VERSION 5.7 ;
BUSBITCHARS "[]" ;
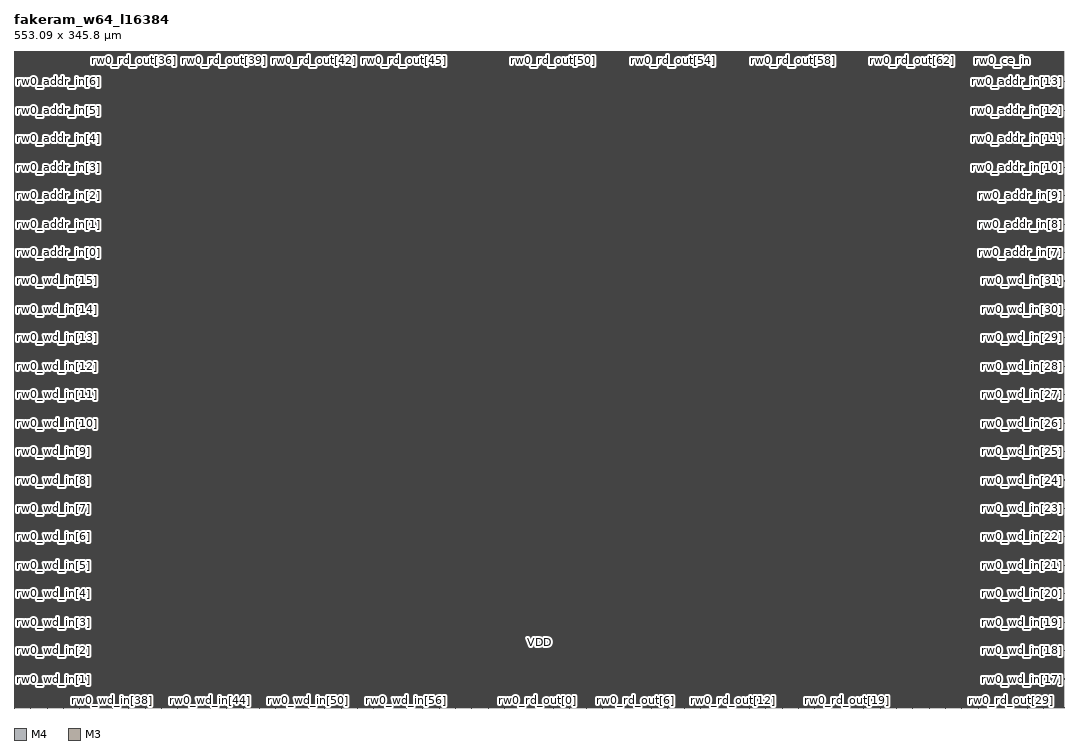
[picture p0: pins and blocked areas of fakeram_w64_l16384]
MACRO fakeram_w64_l16384
  FOREIGN fakeram_w64_l16384 0 0 ;
  SYMMETRY X Y R90 ;
  SIZE 553.090 BY 345.800 ;
  CLASS BLOCK ;
  PIN rw0_wd_in[0]
    DIRECTION INPUT ;
    USE SIGNAL ;
    SHAPE ABUTMENT ;
    PORT
      LAYER M4 ;
      RECT 0.000 0.276 0.072 0.300 ;
    END
  END rw0_wd_in[0]
  PIN rw0_wd_in[1]
    DIRECTION INPUT ;
    USE SIGNAL ;
    SHAPE ABUTMENT ;
    PORT
      LAYER M4 ;
      RECT 0.000 15.252 0.072 15.276 ;
    END
  END rw0_wd_in[1]
  PIN rw0_wd_in[2]
    DIRECTION INPUT ;
    USE SIGNAL ;
    SHAPE ABUTMENT ;
    PORT
      LAYER M4 ;
      RECT 0.000 30.228 0.072 30.252 ;
    END
  END rw0_wd_in[2]
  PIN rw0_wd_in[3]
    DIRECTION INPUT ;
    USE SIGNAL ;
    SHAPE ABUTMENT ;
    PORT
      LAYER M4 ;
      RECT 0.000 45.204 0.072 45.228 ;
    END
  END rw0_wd_in[3]
  PIN rw0_wd_in[4]
    DIRECTION INPUT ;
    USE SIGNAL ;
    SHAPE ABUTMENT ;
    PORT
      LAYER M4 ;
      RECT 0.000 60.180 0.072 60.204 ;
    END
  END rw0_wd_in[4]
  PIN rw0_wd_in[5]
    DIRECTION INPUT ;
    USE SIGNAL ;
    SHAPE ABUTMENT ;
    PORT
      LAYER M4 ;
      RECT 0.000 75.156 0.072 75.180 ;
    END
  END rw0_wd_in[5]
  PIN rw0_wd_in[6]
    DIRECTION INPUT ;
    USE SIGNAL ;
    SHAPE ABUTMENT ;
    PORT
      LAYER M4 ;
      RECT 0.000 90.132 0.072 90.156 ;
    END
  END rw0_wd_in[6]
  PIN rw0_wd_in[7]
    DIRECTION INPUT ;
    USE SIGNAL ;
    SHAPE ABUTMENT ;
    PORT
      LAYER M4 ;
      RECT 0.000 105.108 0.072 105.132 ;
    END
  END rw0_wd_in[7]
  PIN rw0_wd_in[8]
    DIRECTION INPUT ;
    USE SIGNAL ;
    SHAPE ABUTMENT ;
    PORT
      LAYER M4 ;
      RECT 0.000 120.084 0.072 120.108 ;
    END
  END rw0_wd_in[8]
  PIN rw0_wd_in[9]
    DIRECTION INPUT ;
    USE SIGNAL ;
    SHAPE ABUTMENT ;
    PORT
      LAYER M4 ;
      RECT 0.000 135.060 0.072 135.084 ;
    END
  END rw0_wd_in[9]
  PIN rw0_wd_in[10]
    DIRECTION INPUT ;
    USE SIGNAL ;
    SHAPE ABUTMENT ;
    PORT
      LAYER M4 ;
      RECT 0.000 150.036 0.072 150.060 ;
    END
  END rw0_wd_in[10]
  PIN rw0_wd_in[11]
    DIRECTION INPUT ;
    USE SIGNAL ;
    SHAPE ABUTMENT ;
    PORT
      LAYER M4 ;
      RECT 0.000 165.012 0.072 165.036 ;
    END
  END rw0_wd_in[11]
  PIN rw0_wd_in[12]
    DIRECTION INPUT ;
    USE SIGNAL ;
    SHAPE ABUTMENT ;
    PORT
      LAYER M4 ;
      RECT 0.000 179.988 0.072 180.012 ;
    END
  END rw0_wd_in[12]
  PIN rw0_wd_in[13]
    DIRECTION INPUT ;
    USE SIGNAL ;
    SHAPE ABUTMENT ;
    PORT
      LAYER M4 ;
      RECT 0.000 194.964 0.072 194.988 ;
    END
  END rw0_wd_in[13]
  PIN rw0_wd_in[14]
    DIRECTION INPUT ;
    USE SIGNAL ;
    SHAPE ABUTMENT ;
    PORT
      LAYER M4 ;
      RECT 0.000 209.940 0.072 209.964 ;
    END
  END rw0_wd_in[14]
  PIN rw0_wd_in[15]
    DIRECTION INPUT ;
    USE SIGNAL ;
    SHAPE ABUTMENT ;
    PORT
      LAYER M4 ;
      RECT 0.000 224.916 0.072 224.940 ;
    END
  END rw0_wd_in[15]
  PIN rw0_wd_in[16]
    DIRECTION INPUT ;
    USE SIGNAL ;
    SHAPE ABUTMENT ;
    PORT
      LAYER M4 ;
      RECT 553.018 0.276 553.090 0.300 ;
    END
  END rw0_wd_in[16]
  PIN rw0_wd_in[17]
    DIRECTION INPUT ;
    USE SIGNAL ;
    SHAPE ABUTMENT ;
    PORT
      LAYER M4 ;
      RECT 553.018 15.252 553.090 15.276 ;
    END
  END rw0_wd_in[17]
  PIN rw0_wd_in[18]
    DIRECTION INPUT ;
    USE SIGNAL ;
    SHAPE ABUTMENT ;
    PORT
      LAYER M4 ;
      RECT 553.018 30.228 553.090 30.252 ;
    END
  END rw0_wd_in[18]
  PIN rw0_wd_in[19]
    DIRECTION INPUT ;
    USE SIGNAL ;
    SHAPE ABUTMENT ;
    PORT
      LAYER M4 ;
      RECT 553.018 45.204 553.090 45.228 ;
    END
  END rw0_wd_in[19]
  PIN rw0_wd_in[20]
    DIRECTION INPUT ;
    USE SIGNAL ;
    SHAPE ABUTMENT ;
    PORT
      LAYER M4 ;
      RECT 553.018 60.180 553.090 60.204 ;
    END
  END rw0_wd_in[20]
  PIN rw0_wd_in[21]
    DIRECTION INPUT ;
    USE SIGNAL ;
    SHAPE ABUTMENT ;
    PORT
      LAYER M4 ;
      RECT 553.018 75.156 553.090 75.180 ;
    END
  END rw0_wd_in[21]
  PIN rw0_wd_in[22]
    DIRECTION INPUT ;
    USE SIGNAL ;
    SHAPE ABUTMENT ;
    PORT
      LAYER M4 ;
      RECT 553.018 90.132 553.090 90.156 ;
    END
  END rw0_wd_in[22]
  PIN rw0_wd_in[23]
    DIRECTION INPUT ;
    USE SIGNAL ;
    SHAPE ABUTMENT ;
    PORT
      LAYER M4 ;
      RECT 553.018 105.108 553.090 105.132 ;
    END
  END rw0_wd_in[23]
  PIN rw0_wd_in[24]
    DIRECTION INPUT ;
    USE SIGNAL ;
    SHAPE ABUTMENT ;
    PORT
      LAYER M4 ;
      RECT 553.018 120.084 553.090 120.108 ;
    END
  END rw0_wd_in[24]
  PIN rw0_wd_in[25]
    DIRECTION INPUT ;
    USE SIGNAL ;
    SHAPE ABUTMENT ;
    PORT
      LAYER M4 ;
      RECT 553.018 135.060 553.090 135.084 ;
    END
  END rw0_wd_in[25]
  PIN rw0_wd_in[26]
    DIRECTION INPUT ;
    USE SIGNAL ;
    SHAPE ABUTMENT ;
    PORT
      LAYER M4 ;
      RECT 553.018 150.036 553.090 150.060 ;
    END
  END rw0_wd_in[26]
  PIN rw0_wd_in[27]
    DIRECTION INPUT ;
    USE SIGNAL ;
    SHAPE ABUTMENT ;
    PORT
      LAYER M4 ;
      RECT 553.018 165.012 553.090 165.036 ;
    END
  END rw0_wd_in[27]
  PIN rw0_wd_in[28]
    DIRECTION INPUT ;
    USE SIGNAL ;
    SHAPE ABUTMENT ;
    PORT
      LAYER M4 ;
      RECT 553.018 179.988 553.090 180.012 ;
    END
  END rw0_wd_in[28]
  PIN rw0_wd_in[29]
    DIRECTION INPUT ;
    USE SIGNAL ;
    SHAPE ABUTMENT ;
    PORT
      LAYER M4 ;
      RECT 553.018 194.964 553.090 194.988 ;
    END
  END rw0_wd_in[29]
  PIN rw0_wd_in[30]
    DIRECTION INPUT ;
    USE SIGNAL ;
    SHAPE ABUTMENT ;
    PORT
      LAYER M4 ;
      RECT 553.018 209.940 553.090 209.964 ;
    END
  END rw0_wd_in[30]
  PIN rw0_wd_in[31]
    DIRECTION INPUT ;
    USE SIGNAL ;
    SHAPE ABUTMENT ;
    PORT
      LAYER M4 ;
      RECT 553.018 224.916 553.090 224.940 ;
    END
  END rw0_wd_in[31]
  PIN rw0_wd_in[32]
    DIRECTION INPUT ;
    USE SIGNAL ;
    SHAPE ABUTMENT ;
    PORT
      LAYER M3 ;
      RECT 0.207 0.000 0.225 0.054 ;
    END
  END rw0_wd_in[32]
  PIN rw0_wd_in[33]
    DIRECTION INPUT ;
    USE SIGNAL ;
    SHAPE ABUTMENT ;
    PORT
      LAYER M3 ;
      RECT 8.811 0.000 8.829 0.054 ;
    END
  END rw0_wd_in[33]
  PIN rw0_wd_in[34]
    DIRECTION INPUT ;
    USE SIGNAL ;
    SHAPE ABUTMENT ;
    PORT
      LAYER M3 ;
      RECT 17.415 0.000 17.433 0.054 ;
    END
  END rw0_wd_in[34]
  PIN rw0_wd_in[35]
    DIRECTION INPUT ;
    USE SIGNAL ;
    SHAPE ABUTMENT ;
    PORT
      LAYER M3 ;
      RECT 26.019 0.000 26.037 0.054 ;
    END
  END rw0_wd_in[35]
  PIN rw0_wd_in[36]
    DIRECTION INPUT ;
    USE SIGNAL ;
    SHAPE ABUTMENT ;
    PORT
      LAYER M3 ;
      RECT 34.623 0.000 34.641 0.054 ;
    END
  END rw0_wd_in[36]
  PIN rw0_wd_in[37]
    DIRECTION INPUT ;
    USE SIGNAL ;
    SHAPE ABUTMENT ;
    PORT
      LAYER M3 ;
      RECT 43.227 0.000 43.245 0.054 ;
    END
  END rw0_wd_in[37]
  PIN rw0_wd_in[38]
    DIRECTION INPUT ;
    USE SIGNAL ;
    SHAPE ABUTMENT ;
    PORT
      LAYER M3 ;
      RECT 51.831 0.000 51.849 0.054 ;
    END
  END rw0_wd_in[38]
  PIN rw0_wd_in[39]
    DIRECTION INPUT ;
    USE SIGNAL ;
    SHAPE ABUTMENT ;
    PORT
      LAYER M3 ;
      RECT 60.435 0.000 60.453 0.054 ;
    END
  END rw0_wd_in[39]
  PIN rw0_wd_in[40]
    DIRECTION INPUT ;
    USE SIGNAL ;
    SHAPE ABUTMENT ;
    PORT
      LAYER M3 ;
      RECT 69.039 0.000 69.057 0.054 ;
    END
  END rw0_wd_in[40]
  PIN rw0_wd_in[41]
    DIRECTION INPUT ;
    USE SIGNAL ;
    SHAPE ABUTMENT ;
    PORT
      LAYER M3 ;
      RECT 77.643 0.000 77.661 0.054 ;
    END
  END rw0_wd_in[41]
  PIN rw0_wd_in[42]
    DIRECTION INPUT ;
    USE SIGNAL ;
    SHAPE ABUTMENT ;
    PORT
      LAYER M3 ;
      RECT 86.247 0.000 86.265 0.054 ;
    END
  END rw0_wd_in[42]
  PIN rw0_wd_in[43]
    DIRECTION INPUT ;
    USE SIGNAL ;
    SHAPE ABUTMENT ;
    PORT
      LAYER M3 ;
      RECT 94.851 0.000 94.869 0.054 ;
    END
  END rw0_wd_in[43]
  PIN rw0_wd_in[44]
    DIRECTION INPUT ;
    USE SIGNAL ;
    SHAPE ABUTMENT ;
    PORT
      LAYER M3 ;
      RECT 103.455 0.000 103.473 0.054 ;
    END
  END rw0_wd_in[44]
  PIN rw0_wd_in[45]
    DIRECTION INPUT ;
    USE SIGNAL ;
    SHAPE ABUTMENT ;
    PORT
      LAYER M3 ;
      RECT 112.059 0.000 112.077 0.054 ;
    END
  END rw0_wd_in[45]
  PIN rw0_wd_in[46]
    DIRECTION INPUT ;
    USE SIGNAL ;
    SHAPE ABUTMENT ;
    PORT
      LAYER M3 ;
      RECT 120.663 0.000 120.681 0.054 ;
    END
  END rw0_wd_in[46]
  PIN rw0_wd_in[47]
    DIRECTION INPUT ;
    USE SIGNAL ;
    SHAPE ABUTMENT ;
    PORT
      LAYER M3 ;
      RECT 129.267 0.000 129.285 0.054 ;
    END
  END rw0_wd_in[47]
  PIN rw0_wd_in[48]
    DIRECTION INPUT ;
    USE SIGNAL ;
    SHAPE ABUTMENT ;
    PORT
      LAYER M3 ;
      RECT 137.871 0.000 137.889 0.054 ;
    END
  END rw0_wd_in[48]
  PIN rw0_wd_in[49]
    DIRECTION INPUT ;
    USE SIGNAL ;
    SHAPE ABUTMENT ;
    PORT
      LAYER M3 ;
      RECT 146.475 0.000 146.493 0.054 ;
    END
  END rw0_wd_in[49]
  PIN rw0_wd_in[50]
    DIRECTION INPUT ;
    USE SIGNAL ;
    SHAPE ABUTMENT ;
    PORT
      LAYER M3 ;
      RECT 155.079 0.000 155.097 0.054 ;
    END
  END rw0_wd_in[50]
  PIN rw0_wd_in[51]
    DIRECTION INPUT ;
    USE SIGNAL ;
    SHAPE ABUTMENT ;
    PORT
      LAYER M3 ;
      RECT 163.683 0.000 163.701 0.054 ;
    END
  END rw0_wd_in[51]
  PIN rw0_wd_in[52]
    DIRECTION INPUT ;
    USE SIGNAL ;
    SHAPE ABUTMENT ;
    PORT
      LAYER M3 ;
      RECT 172.287 0.000 172.305 0.054 ;
    END
  END rw0_wd_in[52]
  PIN rw0_wd_in[53]
    DIRECTION INPUT ;
    USE SIGNAL ;
    SHAPE ABUTMENT ;
    PORT
      LAYER M3 ;
      RECT 180.891 0.000 180.909 0.054 ;
    END
  END rw0_wd_in[53]
  PIN rw0_wd_in[54]
    DIRECTION INPUT ;
    USE SIGNAL ;
    SHAPE ABUTMENT ;
    PORT
      LAYER M3 ;
      RECT 189.495 0.000 189.513 0.054 ;
    END
  END rw0_wd_in[54]
  PIN rw0_wd_in[55]
    DIRECTION INPUT ;
    USE SIGNAL ;
    SHAPE ABUTMENT ;
    PORT
      LAYER M3 ;
      RECT 198.099 0.000 198.117 0.054 ;
    END
  END rw0_wd_in[55]
  PIN rw0_wd_in[56]
    DIRECTION INPUT ;
    USE SIGNAL ;
    SHAPE ABUTMENT ;
    PORT
      LAYER M3 ;
      RECT 206.703 0.000 206.721 0.054 ;
    END
  END rw0_wd_in[56]
  PIN rw0_wd_in[57]
    DIRECTION INPUT ;
    USE SIGNAL ;
    SHAPE ABUTMENT ;
    PORT
      LAYER M3 ;
      RECT 215.307 0.000 215.325 0.054 ;
    END
  END rw0_wd_in[57]
  PIN rw0_wd_in[58]
    DIRECTION INPUT ;
    USE SIGNAL ;
    SHAPE ABUTMENT ;
    PORT
      LAYER M3 ;
      RECT 223.911 0.000 223.929 0.054 ;
    END
  END rw0_wd_in[58]
  PIN rw0_wd_in[59]
    DIRECTION INPUT ;
    USE SIGNAL ;
    SHAPE ABUTMENT ;
    PORT
      LAYER M3 ;
      RECT 232.515 0.000 232.533 0.054 ;
    END
  END rw0_wd_in[59]
  PIN rw0_wd_in[60]
    DIRECTION INPUT ;
    USE SIGNAL ;
    SHAPE ABUTMENT ;
    PORT
      LAYER M3 ;
      RECT 241.119 0.000 241.137 0.054 ;
    END
  END rw0_wd_in[60]
  PIN rw0_wd_in[61]
    DIRECTION INPUT ;
    USE SIGNAL ;
    SHAPE ABUTMENT ;
    PORT
      LAYER M3 ;
      RECT 249.723 0.000 249.741 0.054 ;
    END
  END rw0_wd_in[61]
  PIN rw0_wd_in[62]
    DIRECTION INPUT ;
    USE SIGNAL ;
    SHAPE ABUTMENT ;
    PORT
      LAYER M3 ;
      RECT 258.327 0.000 258.345 0.054 ;
    END
  END rw0_wd_in[62]
  PIN rw0_wd_in[63]
    DIRECTION INPUT ;
    USE SIGNAL ;
    SHAPE ABUTMENT ;
    PORT
      LAYER M3 ;
      RECT 266.931 0.000 266.949 0.054 ;
    END
  END rw0_wd_in[63]
  PIN rw0_rd_out[0]
    DIRECTION OUTPUT ;
    USE SIGNAL ;
    SHAPE ABUTMENT ;
    PORT
      LAYER M3 ;
      RECT 275.535 0.000 275.553 0.054 ;
    END
  END rw0_rd_out[0]
  PIN rw0_rd_out[1]
    DIRECTION OUTPUT ;
    USE SIGNAL ;
    SHAPE ABUTMENT ;
    PORT
      LAYER M3 ;
      RECT 284.139 0.000 284.157 0.054 ;
    END
  END rw0_rd_out[1]
  PIN rw0_rd_out[2]
    DIRECTION OUTPUT ;
    USE SIGNAL ;
    SHAPE ABUTMENT ;
    PORT
      LAYER M3 ;
      RECT 292.743 0.000 292.761 0.054 ;
    END
  END rw0_rd_out[2]
  PIN rw0_rd_out[3]
    DIRECTION OUTPUT ;
    USE SIGNAL ;
    SHAPE ABUTMENT ;
    PORT
      LAYER M3 ;
      RECT 301.347 0.000 301.365 0.054 ;
    END
  END rw0_rd_out[3]
  PIN rw0_rd_out[4]
    DIRECTION OUTPUT ;
    USE SIGNAL ;
    SHAPE ABUTMENT ;
    PORT
      LAYER M3 ;
      RECT 309.951 0.000 309.969 0.054 ;
    END
  END rw0_rd_out[4]
  PIN rw0_rd_out[5]
    DIRECTION OUTPUT ;
    USE SIGNAL ;
    SHAPE ABUTMENT ;
    PORT
      LAYER M3 ;
      RECT 318.555 0.000 318.573 0.054 ;
    END
  END rw0_rd_out[5]
  PIN rw0_rd_out[6]
    DIRECTION OUTPUT ;
    USE SIGNAL ;
    SHAPE ABUTMENT ;
    PORT
      LAYER M3 ;
      RECT 327.159 0.000 327.177 0.054 ;
    END
  END rw0_rd_out[6]
  PIN rw0_rd_out[7]
    DIRECTION OUTPUT ;
    USE SIGNAL ;
    SHAPE ABUTMENT ;
    PORT
      LAYER M3 ;
      RECT 335.763 0.000 335.781 0.054 ;
    END
  END rw0_rd_out[7]
  PIN rw0_rd_out[8]
    DIRECTION OUTPUT ;
    USE SIGNAL ;
    SHAPE ABUTMENT ;
    PORT
      LAYER M3 ;
      RECT 344.367 0.000 344.385 0.054 ;
    END
  END rw0_rd_out[8]
  PIN rw0_rd_out[9]
    DIRECTION OUTPUT ;
    USE SIGNAL ;
    SHAPE ABUTMENT ;
    PORT
      LAYER M3 ;
      RECT 352.971 0.000 352.989 0.054 ;
    END
  END rw0_rd_out[9]
  PIN rw0_rd_out[10]
    DIRECTION OUTPUT ;
    USE SIGNAL ;
    SHAPE ABUTMENT ;
    PORT
      LAYER M3 ;
      RECT 361.575 0.000 361.593 0.054 ;
    END
  END rw0_rd_out[10]
  PIN rw0_rd_out[11]
    DIRECTION OUTPUT ;
    USE SIGNAL ;
    SHAPE ABUTMENT ;
    PORT
      LAYER M3 ;
      RECT 370.179 0.000 370.197 0.054 ;
    END
  END rw0_rd_out[11]
  PIN rw0_rd_out[12]
    DIRECTION OUTPUT ;
    USE SIGNAL ;
    SHAPE ABUTMENT ;
    PORT
      LAYER M3 ;
      RECT 378.783 0.000 378.801 0.054 ;
    END
  END rw0_rd_out[12]
  PIN rw0_rd_out[13]
    DIRECTION OUTPUT ;
    USE SIGNAL ;
    SHAPE ABUTMENT ;
    PORT
      LAYER M3 ;
      RECT 387.387 0.000 387.405 0.054 ;
    END
  END rw0_rd_out[13]
  PIN rw0_rd_out[14]
    DIRECTION OUTPUT ;
    USE SIGNAL ;
    SHAPE ABUTMENT ;
    PORT
      LAYER M3 ;
      RECT 395.991 0.000 396.009 0.054 ;
    END
  END rw0_rd_out[14]
  PIN rw0_rd_out[15]
    DIRECTION OUTPUT ;
    USE SIGNAL ;
    SHAPE ABUTMENT ;
    PORT
      LAYER M3 ;
      RECT 404.595 0.000 404.613 0.054 ;
    END
  END rw0_rd_out[15]
  PIN rw0_rd_out[16]
    DIRECTION OUTPUT ;
    USE SIGNAL ;
    SHAPE ABUTMENT ;
    PORT
      LAYER M3 ;
      RECT 413.199 0.000 413.217 0.054 ;
    END
  END rw0_rd_out[16]
  PIN rw0_rd_out[17]
    DIRECTION OUTPUT ;
    USE SIGNAL ;
    SHAPE ABUTMENT ;
    PORT
      LAYER M3 ;
      RECT 421.803 0.000 421.821 0.054 ;
    END
  END rw0_rd_out[17]
  PIN rw0_rd_out[18]
    DIRECTION OUTPUT ;
    USE SIGNAL ;
    SHAPE ABUTMENT ;
    PORT
      LAYER M3 ;
      RECT 430.407 0.000 430.425 0.054 ;
    END
  END rw0_rd_out[18]
  PIN rw0_rd_out[19]
    DIRECTION OUTPUT ;
    USE SIGNAL ;
    SHAPE ABUTMENT ;
    PORT
      LAYER M3 ;
      RECT 439.011 0.000 439.029 0.054 ;
    END
  END rw0_rd_out[19]
  PIN rw0_rd_out[20]
    DIRECTION OUTPUT ;
    USE SIGNAL ;
    SHAPE ABUTMENT ;
    PORT
      LAYER M3 ;
      RECT 447.615 0.000 447.633 0.054 ;
    END
  END rw0_rd_out[20]
  PIN rw0_rd_out[21]
    DIRECTION OUTPUT ;
    USE SIGNAL ;
    SHAPE ABUTMENT ;
    PORT
      LAYER M3 ;
      RECT 456.219 0.000 456.237 0.054 ;
    END
  END rw0_rd_out[21]
  PIN rw0_rd_out[22]
    DIRECTION OUTPUT ;
    USE SIGNAL ;
    SHAPE ABUTMENT ;
    PORT
      LAYER M3 ;
      RECT 464.823 0.000 464.841 0.054 ;
    END
  END rw0_rd_out[22]
  PIN rw0_rd_out[23]
    DIRECTION OUTPUT ;
    USE SIGNAL ;
    SHAPE ABUTMENT ;
    PORT
      LAYER M3 ;
      RECT 473.427 0.000 473.445 0.054 ;
    END
  END rw0_rd_out[23]
  PIN rw0_rd_out[24]
    DIRECTION OUTPUT ;
    USE SIGNAL ;
    SHAPE ABUTMENT ;
    PORT
      LAYER M3 ;
      RECT 482.031 0.000 482.049 0.054 ;
    END
  END rw0_rd_out[24]
  PIN rw0_rd_out[25]
    DIRECTION OUTPUT ;
    USE SIGNAL ;
    SHAPE ABUTMENT ;
    PORT
      LAYER M3 ;
      RECT 490.635 0.000 490.653 0.054 ;
    END
  END rw0_rd_out[25]
  PIN rw0_rd_out[26]
    DIRECTION OUTPUT ;
    USE SIGNAL ;
    SHAPE ABUTMENT ;
    PORT
      LAYER M3 ;
      RECT 499.239 0.000 499.257 0.054 ;
    END
  END rw0_rd_out[26]
  PIN rw0_rd_out[27]
    DIRECTION OUTPUT ;
    USE SIGNAL ;
    SHAPE ABUTMENT ;
    PORT
      LAYER M3 ;
      RECT 507.843 0.000 507.861 0.054 ;
    END
  END rw0_rd_out[27]
  PIN rw0_rd_out[28]
    DIRECTION OUTPUT ;
    USE SIGNAL ;
    SHAPE ABUTMENT ;
    PORT
      LAYER M3 ;
      RECT 516.447 0.000 516.465 0.054 ;
    END
  END rw0_rd_out[28]
  PIN rw0_rd_out[29]
    DIRECTION OUTPUT ;
    USE SIGNAL ;
    SHAPE ABUTMENT ;
    PORT
      LAYER M3 ;
      RECT 525.051 0.000 525.069 0.054 ;
    END
  END rw0_rd_out[29]
  PIN rw0_rd_out[30]
    DIRECTION OUTPUT ;
    USE SIGNAL ;
    SHAPE ABUTMENT ;
    PORT
      LAYER M3 ;
      RECT 533.655 0.000 533.673 0.054 ;
    END
  END rw0_rd_out[30]
  PIN rw0_rd_out[31]
    DIRECTION OUTPUT ;
    USE SIGNAL ;
    SHAPE ABUTMENT ;
    PORT
      LAYER M3 ;
      RECT 542.259 0.000 542.277 0.054 ;
    END
  END rw0_rd_out[31]
  PIN rw0_rd_out[32]
    DIRECTION OUTPUT ;
    USE SIGNAL ;
    SHAPE ABUTMENT ;
    PORT
      LAYER M3 ;
      RECT 0.207 345.746 0.225 345.800 ;
    END
  END rw0_rd_out[32]
  PIN rw0_rd_out[33]
    DIRECTION OUTPUT ;
    USE SIGNAL ;
    SHAPE ABUTMENT ;
    PORT
      LAYER M3 ;
      RECT 15.975 345.746 15.993 345.800 ;
    END
  END rw0_rd_out[33]
  PIN rw0_rd_out[34]
    DIRECTION OUTPUT ;
    USE SIGNAL ;
    SHAPE ABUTMENT ;
    PORT
      LAYER M3 ;
      RECT 31.743 345.746 31.761 345.800 ;
    END
  END rw0_rd_out[34]
  PIN rw0_rd_out[35]
    DIRECTION OUTPUT ;
    USE SIGNAL ;
    SHAPE ABUTMENT ;
    PORT
      LAYER M3 ;
      RECT 47.511 345.746 47.529 345.800 ;
    END
  END rw0_rd_out[35]
  PIN rw0_rd_out[36]
    DIRECTION OUTPUT ;
    USE SIGNAL ;
    SHAPE ABUTMENT ;
    PORT
      LAYER M3 ;
      RECT 63.279 345.746 63.297 345.800 ;
    END
  END rw0_rd_out[36]
  PIN rw0_rd_out[37]
    DIRECTION OUTPUT ;
    USE SIGNAL ;
    SHAPE ABUTMENT ;
    PORT
      LAYER M3 ;
      RECT 79.047 345.746 79.065 345.800 ;
    END
  END rw0_rd_out[37]
  PIN rw0_rd_out[38]
    DIRECTION OUTPUT ;
    USE SIGNAL ;
    SHAPE ABUTMENT ;
    PORT
      LAYER M3 ;
      RECT 94.815 345.746 94.833 345.800 ;
    END
  END rw0_rd_out[38]
  PIN rw0_rd_out[39]
    DIRECTION OUTPUT ;
    USE SIGNAL ;
    SHAPE ABUTMENT ;
    PORT
      LAYER M3 ;
      RECT 110.583 345.746 110.601 345.800 ;
    END
  END rw0_rd_out[39]
  PIN rw0_rd_out[40]
    DIRECTION OUTPUT ;
    USE SIGNAL ;
    SHAPE ABUTMENT ;
    PORT
      LAYER M3 ;
      RECT 126.351 345.746 126.369 345.800 ;
    END
  END rw0_rd_out[40]
  PIN rw0_rd_out[41]
    DIRECTION OUTPUT ;
    USE SIGNAL ;
    SHAPE ABUTMENT ;
    PORT
      LAYER M3 ;
      RECT 142.119 345.746 142.137 345.800 ;
    END
  END rw0_rd_out[41]
  PIN rw0_rd_out[42]
    DIRECTION OUTPUT ;
    USE SIGNAL ;
    SHAPE ABUTMENT ;
    PORT
      LAYER M3 ;
      RECT 157.887 345.746 157.905 345.800 ;
    END
  END rw0_rd_out[42]
  PIN rw0_rd_out[43]
    DIRECTION OUTPUT ;
    USE SIGNAL ;
    SHAPE ABUTMENT ;
    PORT
      LAYER M3 ;
      RECT 173.655 345.746 173.673 345.800 ;
    END
  END rw0_rd_out[43]
  PIN rw0_rd_out[44]
    DIRECTION OUTPUT ;
    USE SIGNAL ;
    SHAPE ABUTMENT ;
    PORT
      LAYER M3 ;
      RECT 189.423 345.746 189.441 345.800 ;
    END
  END rw0_rd_out[44]
  PIN rw0_rd_out[45]
    DIRECTION OUTPUT ;
    USE SIGNAL ;
    SHAPE ABUTMENT ;
    PORT
      LAYER M3 ;
      RECT 205.191 345.746 205.209 345.800 ;
    END
  END rw0_rd_out[45]
  PIN rw0_rd_out[46]
    DIRECTION OUTPUT ;
    USE SIGNAL ;
    SHAPE ABUTMENT ;
    PORT
      LAYER M3 ;
      RECT 220.959 345.746 220.977 345.800 ;
    END
  END rw0_rd_out[46]
  PIN rw0_rd_out[47]
    DIRECTION OUTPUT ;
    USE SIGNAL ;
    SHAPE ABUTMENT ;
    PORT
      LAYER M3 ;
      RECT 236.727 345.746 236.745 345.800 ;
    END
  END rw0_rd_out[47]
  PIN rw0_rd_out[48]
    DIRECTION OUTPUT ;
    USE SIGNAL ;
    SHAPE ABUTMENT ;
    PORT
      LAYER M3 ;
      RECT 252.495 345.746 252.513 345.800 ;
    END
  END rw0_rd_out[48]
  PIN rw0_rd_out[49]
    DIRECTION OUTPUT ;
    USE SIGNAL ;
    SHAPE ABUTMENT ;
    PORT
      LAYER M3 ;
      RECT 268.263 345.746 268.281 345.800 ;
    END
  END rw0_rd_out[49]
  PIN rw0_rd_out[50]
    DIRECTION OUTPUT ;
    USE SIGNAL ;
    SHAPE ABUTMENT ;
    PORT
      LAYER M3 ;
      RECT 284.031 345.746 284.049 345.800 ;
    END
  END rw0_rd_out[50]
  PIN rw0_rd_out[51]
    DIRECTION OUTPUT ;
    USE SIGNAL ;
    SHAPE ABUTMENT ;
    PORT
      LAYER M3 ;
      RECT 299.799 345.746 299.817 345.800 ;
    END
  END rw0_rd_out[51]
  PIN rw0_rd_out[52]
    DIRECTION OUTPUT ;
    USE SIGNAL ;
    SHAPE ABUTMENT ;
    PORT
      LAYER M3 ;
      RECT 315.567 345.746 315.585 345.800 ;
    END
  END rw0_rd_out[52]
  PIN rw0_rd_out[53]
    DIRECTION OUTPUT ;
    USE SIGNAL ;
    SHAPE ABUTMENT ;
    PORT
      LAYER M3 ;
      RECT 331.335 345.746 331.353 345.800 ;
    END
  END rw0_rd_out[53]
  PIN rw0_rd_out[54]
    DIRECTION OUTPUT ;
    USE SIGNAL ;
    SHAPE ABUTMENT ;
    PORT
      LAYER M3 ;
      RECT 347.103 345.746 347.121 345.800 ;
    END
  END rw0_rd_out[54]
  PIN rw0_rd_out[55]
    DIRECTION OUTPUT ;
    USE SIGNAL ;
    SHAPE ABUTMENT ;
    PORT
      LAYER M3 ;
      RECT 362.871 345.746 362.889 345.800 ;
    END
  END rw0_rd_out[55]
  PIN rw0_rd_out[56]
    DIRECTION OUTPUT ;
    USE SIGNAL ;
    SHAPE ABUTMENT ;
    PORT
      LAYER M3 ;
      RECT 378.639 345.746 378.657 345.800 ;
    END
  END rw0_rd_out[56]
  PIN rw0_rd_out[57]
    DIRECTION OUTPUT ;
    USE SIGNAL ;
    SHAPE ABUTMENT ;
    PORT
      LAYER M3 ;
      RECT 394.407 345.746 394.425 345.800 ;
    END
  END rw0_rd_out[57]
  PIN rw0_rd_out[58]
    DIRECTION OUTPUT ;
    USE SIGNAL ;
    SHAPE ABUTMENT ;
    PORT
      LAYER M3 ;
      RECT 410.175 345.746 410.193 345.800 ;
    END
  END rw0_rd_out[58]
  PIN rw0_rd_out[59]
    DIRECTION OUTPUT ;
    USE SIGNAL ;
    SHAPE ABUTMENT ;
    PORT
      LAYER M3 ;
      RECT 425.943 345.746 425.961 345.800 ;
    END
  END rw0_rd_out[59]
  PIN rw0_rd_out[60]
    DIRECTION OUTPUT ;
    USE SIGNAL ;
    SHAPE ABUTMENT ;
    PORT
      LAYER M3 ;
      RECT 441.711 345.746 441.729 345.800 ;
    END
  END rw0_rd_out[60]
  PIN rw0_rd_out[61]
    DIRECTION OUTPUT ;
    USE SIGNAL ;
    SHAPE ABUTMENT ;
    PORT
      LAYER M3 ;
      RECT 457.479 345.746 457.497 345.800 ;
    END
  END rw0_rd_out[61]
  PIN rw0_rd_out[62]
    DIRECTION OUTPUT ;
    USE SIGNAL ;
    SHAPE ABUTMENT ;
    PORT
      LAYER M3 ;
      RECT 473.247 345.746 473.265 345.800 ;
    END
  END rw0_rd_out[62]
  PIN rw0_rd_out[63]
    DIRECTION OUTPUT ;
    USE SIGNAL ;
    SHAPE ABUTMENT ;
    PORT
      LAYER M3 ;
      RECT 489.015 345.746 489.033 345.800 ;
    END
  END rw0_rd_out[63]
  PIN rw0_addr_in[0]
    DIRECTION INPUT ;
    USE SIGNAL ;
    SHAPE ABUTMENT ;
    PORT
      LAYER M4 ;
      RECT 0.000 239.892 0.072 239.916 ;
    END
  END rw0_addr_in[0]
  PIN rw0_addr_in[1]
    DIRECTION INPUT ;
    USE SIGNAL ;
    SHAPE ABUTMENT ;
    PORT
      LAYER M4 ;
      RECT 0.000 254.868 0.072 254.892 ;
    END
  END rw0_addr_in[1]
  PIN rw0_addr_in[2]
    DIRECTION INPUT ;
    USE SIGNAL ;
    SHAPE ABUTMENT ;
    PORT
      LAYER M4 ;
      RECT 0.000 269.844 0.072 269.868 ;
    END
  END rw0_addr_in[2]
  PIN rw0_addr_in[3]
    DIRECTION INPUT ;
    USE SIGNAL ;
    SHAPE ABUTMENT ;
    PORT
      LAYER M4 ;
      RECT 0.000 284.820 0.072 284.844 ;
    END
  END rw0_addr_in[3]
  PIN rw0_addr_in[4]
    DIRECTION INPUT ;
    USE SIGNAL ;
    SHAPE ABUTMENT ;
    PORT
      LAYER M4 ;
      RECT 0.000 299.796 0.072 299.820 ;
    END
  END rw0_addr_in[4]
  PIN rw0_addr_in[5]
    DIRECTION INPUT ;
    USE SIGNAL ;
    SHAPE ABUTMENT ;
    PORT
      LAYER M4 ;
      RECT 0.000 314.772 0.072 314.796 ;
    END
  END rw0_addr_in[5]
  PIN rw0_addr_in[6]
    DIRECTION INPUT ;
    USE SIGNAL ;
    SHAPE ABUTMENT ;
    PORT
      LAYER M4 ;
      RECT 0.000 329.748 0.072 329.772 ;
    END
  END rw0_addr_in[6]
  PIN rw0_addr_in[7]
    DIRECTION INPUT ;
    USE SIGNAL ;
    SHAPE ABUTMENT ;
    PORT
      LAYER M4 ;
      RECT 553.018 239.892 553.090 239.916 ;
    END
  END rw0_addr_in[7]
  PIN rw0_addr_in[8]
    DIRECTION INPUT ;
    USE SIGNAL ;
    SHAPE ABUTMENT ;
    PORT
      LAYER M4 ;
      RECT 553.018 254.868 553.090 254.892 ;
    END
  END rw0_addr_in[8]
  PIN rw0_addr_in[9]
    DIRECTION INPUT ;
    USE SIGNAL ;
    SHAPE ABUTMENT ;
    PORT
      LAYER M4 ;
      RECT 553.018 269.844 553.090 269.868 ;
    END
  END rw0_addr_in[9]
  PIN rw0_addr_in[10]
    DIRECTION INPUT ;
    USE SIGNAL ;
    SHAPE ABUTMENT ;
    PORT
      LAYER M4 ;
      RECT 553.018 284.820 553.090 284.844 ;
    END
  END rw0_addr_in[10]
  PIN rw0_addr_in[11]
    DIRECTION INPUT ;
    USE SIGNAL ;
    SHAPE ABUTMENT ;
    PORT
      LAYER M4 ;
      RECT 553.018 299.796 553.090 299.820 ;
    END
  END rw0_addr_in[11]
  PIN rw0_addr_in[12]
    DIRECTION INPUT ;
    USE SIGNAL ;
    SHAPE ABUTMENT ;
    PORT
      LAYER M4 ;
      RECT 553.018 314.772 553.090 314.796 ;
    END
  END rw0_addr_in[12]
  PIN rw0_addr_in[13]
    DIRECTION INPUT ;
    USE SIGNAL ;
    SHAPE ABUTMENT ;
    PORT
      LAYER M4 ;
      RECT 553.018 329.748 553.090 329.772 ;
    END
  END rw0_addr_in[13]
  PIN rw0_we_in
    DIRECTION INPUT ;
    USE SIGNAL ;
    SHAPE ABUTMENT ;
    PORT
      LAYER M3 ;
      RECT 504.783 345.746 504.801 345.800 ;
    END
  END rw0_we_in
  PIN rw0_ce_in
    DIRECTION INPUT ;
    USE SIGNAL ;
    SHAPE ABUTMENT ;
    PORT
      LAYER M3 ;
      RECT 520.551 345.746 520.569 345.800 ;
    END
  END rw0_ce_in
  PIN rw0_clk
    DIRECTION INPUT ;
    USE SIGNAL ;
    SHAPE ABUTMENT ;
    PORT
      LAYER M3 ;
      RECT 536.319 345.746 536.337 345.800 ;
    END
  END rw0_clk
  PIN VSS
    DIRECTION INOUT ;
    USE GROUND ;
    PORT
      LAYER M4 ;
      RECT 0.216 0.240 552.874 0.336 ;
      RECT 0.216 1.008 552.874 1.104 ;
      RECT 0.216 1.776 552.874 1.872 ;
      RECT 0.216 2.544 552.874 2.640 ;
      RECT 0.216 3.312 552.874 3.408 ;
      RECT 0.216 4.080 552.874 4.176 ;
      RECT 0.216 4.848 552.874 4.944 ;
      RECT 0.216 5.616 552.874 5.712 ;
      RECT 0.216 6.384 552.874 6.480 ;
      RECT 0.216 7.152 552.874 7.248 ;
      RECT 0.216 7.920 552.874 8.016 ;
      RECT 0.216 8.688 552.874 8.784 ;
      RECT 0.216 9.456 552.874 9.552 ;
      RECT 0.216 10.224 552.874 10.320 ;
      RECT 0.216 10.992 552.874 11.088 ;
      RECT 0.216 11.760 552.874 11.856 ;
      RECT 0.216 12.528 552.874 12.624 ;
      RECT 0.216 13.296 552.874 13.392 ;
      RECT 0.216 14.064 552.874 14.160 ;
      RECT 0.216 14.832 552.874 14.928 ;
      RECT 0.216 15.600 552.874 15.696 ;
      RECT 0.216 16.368 552.874 16.464 ;
      RECT 0.216 17.136 552.874 17.232 ;
      RECT 0.216 17.904 552.874 18.000 ;
      RECT 0.216 18.672 552.874 18.768 ;
      RECT 0.216 19.440 552.874 19.536 ;
      RECT 0.216 20.208 552.874 20.304 ;
      RECT 0.216 20.976 552.874 21.072 ;
      RECT 0.216 21.744 552.874 21.840 ;
      RECT 0.216 22.512 552.874 22.608 ;
      RECT 0.216 23.280 552.874 23.376 ;
      RECT 0.216 24.048 552.874 24.144 ;
      RECT 0.216 24.816 552.874 24.912 ;
      RECT 0.216 25.584 552.874 25.680 ;
      RECT 0.216 26.352 552.874 26.448 ;
      RECT 0.216 27.120 552.874 27.216 ;
      RECT 0.216 27.888 552.874 27.984 ;
      RECT 0.216 28.656 552.874 28.752 ;
      RECT 0.216 29.424 552.874 29.520 ;
      RECT 0.216 30.192 552.874 30.288 ;
      RECT 0.216 30.960 552.874 31.056 ;
      RECT 0.216 31.728 552.874 31.824 ;
      RECT 0.216 32.496 552.874 32.592 ;
      RECT 0.216 33.264 552.874 33.360 ;
      RECT 0.216 34.032 552.874 34.128 ;
      RECT 0.216 34.800 552.874 34.896 ;
      RECT 0.216 35.568 552.874 35.664 ;
      RECT 0.216 36.336 552.874 36.432 ;
      RECT 0.216 37.104 552.874 37.200 ;
      RECT 0.216 37.872 552.874 37.968 ;
      RECT 0.216 38.640 552.874 38.736 ;
      RECT 0.216 39.408 552.874 39.504 ;
      RECT 0.216 40.176 552.874 40.272 ;
      RECT 0.216 40.944 552.874 41.040 ;
      RECT 0.216 41.712 552.874 41.808 ;
      RECT 0.216 42.480 552.874 42.576 ;
      RECT 0.216 43.248 552.874 43.344 ;
      RECT 0.216 44.016 552.874 44.112 ;
      RECT 0.216 44.784 552.874 44.880 ;
      RECT 0.216 45.552 552.874 45.648 ;
      RECT 0.216 46.320 552.874 46.416 ;
      RECT 0.216 47.088 552.874 47.184 ;
      RECT 0.216 47.856 552.874 47.952 ;
      RECT 0.216 48.624 552.874 48.720 ;
      RECT 0.216 49.392 552.874 49.488 ;
      RECT 0.216 50.160 552.874 50.256 ;
      RECT 0.216 50.928 552.874 51.024 ;
      RECT 0.216 51.696 552.874 51.792 ;
      RECT 0.216 52.464 552.874 52.560 ;
      RECT 0.216 53.232 552.874 53.328 ;
      RECT 0.216 54.000 552.874 54.096 ;
      RECT 0.216 54.768 552.874 54.864 ;
      RECT 0.216 55.536 552.874 55.632 ;
      RECT 0.216 56.304 552.874 56.400 ;
      RECT 0.216 57.072 552.874 57.168 ;
      RECT 0.216 57.840 552.874 57.936 ;
      RECT 0.216 58.608 552.874 58.704 ;
      RECT 0.216 59.376 552.874 59.472 ;
      RECT 0.216 60.144 552.874 60.240 ;
      RECT 0.216 60.912 552.874 61.008 ;
      RECT 0.216 61.680 552.874 61.776 ;
      RECT 0.216 62.448 552.874 62.544 ;
      RECT 0.216 63.216 552.874 63.312 ;
      RECT 0.216 63.984 552.874 64.080 ;
      RECT 0.216 64.752 552.874 64.848 ;
      RECT 0.216 65.520 552.874 65.616 ;
      RECT 0.216 66.288 552.874 66.384 ;
      RECT 0.216 67.056 552.874 67.152 ;
      RECT 0.216 67.824 552.874 67.920 ;
      RECT 0.216 68.592 552.874 68.688 ;
      RECT 0.216 69.360 552.874 69.456 ;
      RECT 0.216 70.128 552.874 70.224 ;
      RECT 0.216 70.896 552.874 70.992 ;
      RECT 0.216 71.664 552.874 71.760 ;
      RECT 0.216 72.432 552.874 72.528 ;
      RECT 0.216 73.200 552.874 73.296 ;
      RECT 0.216 73.968 552.874 74.064 ;
      RECT 0.216 74.736 552.874 74.832 ;
      RECT 0.216 75.504 552.874 75.600 ;
      RECT 0.216 76.272 552.874 76.368 ;
      RECT 0.216 77.040 552.874 77.136 ;
      RECT 0.216 77.808 552.874 77.904 ;
      RECT 0.216 78.576 552.874 78.672 ;
      RECT 0.216 79.344 552.874 79.440 ;
      RECT 0.216 80.112 552.874 80.208 ;
      RECT 0.216 80.880 552.874 80.976 ;
      RECT 0.216 81.648 552.874 81.744 ;
      RECT 0.216 82.416 552.874 82.512 ;
      RECT 0.216 83.184 552.874 83.280 ;
      RECT 0.216 83.952 552.874 84.048 ;
      RECT 0.216 84.720 552.874 84.816 ;
      RECT 0.216 85.488 552.874 85.584 ;
      RECT 0.216 86.256 552.874 86.352 ;
      RECT 0.216 87.024 552.874 87.120 ;
      RECT 0.216 87.792 552.874 87.888 ;
      RECT 0.216 88.560 552.874 88.656 ;
      RECT 0.216 89.328 552.874 89.424 ;
      RECT 0.216 90.096 552.874 90.192 ;
      RECT 0.216 90.864 552.874 90.960 ;
      RECT 0.216 91.632 552.874 91.728 ;
      RECT 0.216 92.400 552.874 92.496 ;
      RECT 0.216 93.168 552.874 93.264 ;
      RECT 0.216 93.936 552.874 94.032 ;
      RECT 0.216 94.704 552.874 94.800 ;
      RECT 0.216 95.472 552.874 95.568 ;
      RECT 0.216 96.240 552.874 96.336 ;
      RECT 0.216 97.008 552.874 97.104 ;
      RECT 0.216 97.776 552.874 97.872 ;
      RECT 0.216 98.544 552.874 98.640 ;
      RECT 0.216 99.312 552.874 99.408 ;
      RECT 0.216 100.080 552.874 100.176 ;
      RECT 0.216 100.848 552.874 100.944 ;
      RECT 0.216 101.616 552.874 101.712 ;
      RECT 0.216 102.384 552.874 102.480 ;
      RECT 0.216 103.152 552.874 103.248 ;
      RECT 0.216 103.920 552.874 104.016 ;
      RECT 0.216 104.688 552.874 104.784 ;
      RECT 0.216 105.456 552.874 105.552 ;
      RECT 0.216 106.224 552.874 106.320 ;
      RECT 0.216 106.992 552.874 107.088 ;
      RECT 0.216 107.760 552.874 107.856 ;
      RECT 0.216 108.528 552.874 108.624 ;
      RECT 0.216 109.296 552.874 109.392 ;
      RECT 0.216 110.064 552.874 110.160 ;
      RECT 0.216 110.832 552.874 110.928 ;
      RECT 0.216 111.600 552.874 111.696 ;
      RECT 0.216 112.368 552.874 112.464 ;
      RECT 0.216 113.136 552.874 113.232 ;
      RECT 0.216 113.904 552.874 114.000 ;
      RECT 0.216 114.672 552.874 114.768 ;
      RECT 0.216 115.440 552.874 115.536 ;
      RECT 0.216 116.208 552.874 116.304 ;
      RECT 0.216 116.976 552.874 117.072 ;
      RECT 0.216 117.744 552.874 117.840 ;
      RECT 0.216 118.512 552.874 118.608 ;
      RECT 0.216 119.280 552.874 119.376 ;
      RECT 0.216 120.048 552.874 120.144 ;
      RECT 0.216 120.816 552.874 120.912 ;
      RECT 0.216 121.584 552.874 121.680 ;
      RECT 0.216 122.352 552.874 122.448 ;
      RECT 0.216 123.120 552.874 123.216 ;
      RECT 0.216 123.888 552.874 123.984 ;
      RECT 0.216 124.656 552.874 124.752 ;
      RECT 0.216 125.424 552.874 125.520 ;
      RECT 0.216 126.192 552.874 126.288 ;
      RECT 0.216 126.960 552.874 127.056 ;
      RECT 0.216 127.728 552.874 127.824 ;
      RECT 0.216 128.496 552.874 128.592 ;
      RECT 0.216 129.264 552.874 129.360 ;
      RECT 0.216 130.032 552.874 130.128 ;
      RECT 0.216 130.800 552.874 130.896 ;
      RECT 0.216 131.568 552.874 131.664 ;
      RECT 0.216 132.336 552.874 132.432 ;
      RECT 0.216 133.104 552.874 133.200 ;
      RECT 0.216 133.872 552.874 133.968 ;
      RECT 0.216 134.640 552.874 134.736 ;
      RECT 0.216 135.408 552.874 135.504 ;
      RECT 0.216 136.176 552.874 136.272 ;
      RECT 0.216 136.944 552.874 137.040 ;
      RECT 0.216 137.712 552.874 137.808 ;
      RECT 0.216 138.480 552.874 138.576 ;
      RECT 0.216 139.248 552.874 139.344 ;
      RECT 0.216 140.016 552.874 140.112 ;
      RECT 0.216 140.784 552.874 140.880 ;
      RECT 0.216 141.552 552.874 141.648 ;
      RECT 0.216 142.320 552.874 142.416 ;
      RECT 0.216 143.088 552.874 143.184 ;
      RECT 0.216 143.856 552.874 143.952 ;
      RECT 0.216 144.624 552.874 144.720 ;
      RECT 0.216 145.392 552.874 145.488 ;
      RECT 0.216 146.160 552.874 146.256 ;
      RECT 0.216 146.928 552.874 147.024 ;
      RECT 0.216 147.696 552.874 147.792 ;
      RECT 0.216 148.464 552.874 148.560 ;
      RECT 0.216 149.232 552.874 149.328 ;
      RECT 0.216 150.000 552.874 150.096 ;
      RECT 0.216 150.768 552.874 150.864 ;
      RECT 0.216 151.536 552.874 151.632 ;
      RECT 0.216 152.304 552.874 152.400 ;
      RECT 0.216 153.072 552.874 153.168 ;
      RECT 0.216 153.840 552.874 153.936 ;
      RECT 0.216 154.608 552.874 154.704 ;
      RECT 0.216 155.376 552.874 155.472 ;
      RECT 0.216 156.144 552.874 156.240 ;
      RECT 0.216 156.912 552.874 157.008 ;
      RECT 0.216 157.680 552.874 157.776 ;
      RECT 0.216 158.448 552.874 158.544 ;
      RECT 0.216 159.216 552.874 159.312 ;
      RECT 0.216 159.984 552.874 160.080 ;
      RECT 0.216 160.752 552.874 160.848 ;
      RECT 0.216 161.520 552.874 161.616 ;
      RECT 0.216 162.288 552.874 162.384 ;
      RECT 0.216 163.056 552.874 163.152 ;
      RECT 0.216 163.824 552.874 163.920 ;
      RECT 0.216 164.592 552.874 164.688 ;
      RECT 0.216 165.360 552.874 165.456 ;
      RECT 0.216 166.128 552.874 166.224 ;
      RECT 0.216 166.896 552.874 166.992 ;
      RECT 0.216 167.664 552.874 167.760 ;
      RECT 0.216 168.432 552.874 168.528 ;
      RECT 0.216 169.200 552.874 169.296 ;
      RECT 0.216 169.968 552.874 170.064 ;
      RECT 0.216 170.736 552.874 170.832 ;
      RECT 0.216 171.504 552.874 171.600 ;
      RECT 0.216 172.272 552.874 172.368 ;
      RECT 0.216 173.040 552.874 173.136 ;
      RECT 0.216 173.808 552.874 173.904 ;
      RECT 0.216 174.576 552.874 174.672 ;
      RECT 0.216 175.344 552.874 175.440 ;
      RECT 0.216 176.112 552.874 176.208 ;
      RECT 0.216 176.880 552.874 176.976 ;
      RECT 0.216 177.648 552.874 177.744 ;
      RECT 0.216 178.416 552.874 178.512 ;
      RECT 0.216 179.184 552.874 179.280 ;
      RECT 0.216 179.952 552.874 180.048 ;
      RECT 0.216 180.720 552.874 180.816 ;
      RECT 0.216 181.488 552.874 181.584 ;
      RECT 0.216 182.256 552.874 182.352 ;
      RECT 0.216 183.024 552.874 183.120 ;
      RECT 0.216 183.792 552.874 183.888 ;
      RECT 0.216 184.560 552.874 184.656 ;
      RECT 0.216 185.328 552.874 185.424 ;
      RECT 0.216 186.096 552.874 186.192 ;
      RECT 0.216 186.864 552.874 186.960 ;
      RECT 0.216 187.632 552.874 187.728 ;
      RECT 0.216 188.400 552.874 188.496 ;
      RECT 0.216 189.168 552.874 189.264 ;
      RECT 0.216 189.936 552.874 190.032 ;
      RECT 0.216 190.704 552.874 190.800 ;
      RECT 0.216 191.472 552.874 191.568 ;
      RECT 0.216 192.240 552.874 192.336 ;
      RECT 0.216 193.008 552.874 193.104 ;
      RECT 0.216 193.776 552.874 193.872 ;
      RECT 0.216 194.544 552.874 194.640 ;
      RECT 0.216 195.312 552.874 195.408 ;
      RECT 0.216 196.080 552.874 196.176 ;
      RECT 0.216 196.848 552.874 196.944 ;
      RECT 0.216 197.616 552.874 197.712 ;
      RECT 0.216 198.384 552.874 198.480 ;
      RECT 0.216 199.152 552.874 199.248 ;
      RECT 0.216 199.920 552.874 200.016 ;
      RECT 0.216 200.688 552.874 200.784 ;
      RECT 0.216 201.456 552.874 201.552 ;
      RECT 0.216 202.224 552.874 202.320 ;
      RECT 0.216 202.992 552.874 203.088 ;
      RECT 0.216 203.760 552.874 203.856 ;
      RECT 0.216 204.528 552.874 204.624 ;
      RECT 0.216 205.296 552.874 205.392 ;
      RECT 0.216 206.064 552.874 206.160 ;
      RECT 0.216 206.832 552.874 206.928 ;
      RECT 0.216 207.600 552.874 207.696 ;
      RECT 0.216 208.368 552.874 208.464 ;
      RECT 0.216 209.136 552.874 209.232 ;
      RECT 0.216 209.904 552.874 210.000 ;
      RECT 0.216 210.672 552.874 210.768 ;
      RECT 0.216 211.440 552.874 211.536 ;
      RECT 0.216 212.208 552.874 212.304 ;
      RECT 0.216 212.976 552.874 213.072 ;
      RECT 0.216 213.744 552.874 213.840 ;
      RECT 0.216 214.512 552.874 214.608 ;
      RECT 0.216 215.280 552.874 215.376 ;
      RECT 0.216 216.048 552.874 216.144 ;
      RECT 0.216 216.816 552.874 216.912 ;
      RECT 0.216 217.584 552.874 217.680 ;
      RECT 0.216 218.352 552.874 218.448 ;
      RECT 0.216 219.120 552.874 219.216 ;
      RECT 0.216 219.888 552.874 219.984 ;
      RECT 0.216 220.656 552.874 220.752 ;
      RECT 0.216 221.424 552.874 221.520 ;
      RECT 0.216 222.192 552.874 222.288 ;
      RECT 0.216 222.960 552.874 223.056 ;
      RECT 0.216 223.728 552.874 223.824 ;
      RECT 0.216 224.496 552.874 224.592 ;
      RECT 0.216 225.264 552.874 225.360 ;
      RECT 0.216 226.032 552.874 226.128 ;
      RECT 0.216 226.800 552.874 226.896 ;
      RECT 0.216 227.568 552.874 227.664 ;
      RECT 0.216 228.336 552.874 228.432 ;
      RECT 0.216 229.104 552.874 229.200 ;
      RECT 0.216 229.872 552.874 229.968 ;
      RECT 0.216 230.640 552.874 230.736 ;
      RECT 0.216 231.408 552.874 231.504 ;
      RECT 0.216 232.176 552.874 232.272 ;
      RECT 0.216 232.944 552.874 233.040 ;
      RECT 0.216 233.712 552.874 233.808 ;
      RECT 0.216 234.480 552.874 234.576 ;
      RECT 0.216 235.248 552.874 235.344 ;
      RECT 0.216 236.016 552.874 236.112 ;
      RECT 0.216 236.784 552.874 236.880 ;
      RECT 0.216 237.552 552.874 237.648 ;
      RECT 0.216 238.320 552.874 238.416 ;
      RECT 0.216 239.088 552.874 239.184 ;
      RECT 0.216 239.856 552.874 239.952 ;
      RECT 0.216 240.624 552.874 240.720 ;
      RECT 0.216 241.392 552.874 241.488 ;
      RECT 0.216 242.160 552.874 242.256 ;
      RECT 0.216 242.928 552.874 243.024 ;
      RECT 0.216 243.696 552.874 243.792 ;
      RECT 0.216 244.464 552.874 244.560 ;
      RECT 0.216 245.232 552.874 245.328 ;
      RECT 0.216 246.000 552.874 246.096 ;
      RECT 0.216 246.768 552.874 246.864 ;
      RECT 0.216 247.536 552.874 247.632 ;
      RECT 0.216 248.304 552.874 248.400 ;
      RECT 0.216 249.072 552.874 249.168 ;
      RECT 0.216 249.840 552.874 249.936 ;
      RECT 0.216 250.608 552.874 250.704 ;
      RECT 0.216 251.376 552.874 251.472 ;
      RECT 0.216 252.144 552.874 252.240 ;
      RECT 0.216 252.912 552.874 253.008 ;
      RECT 0.216 253.680 552.874 253.776 ;
      RECT 0.216 254.448 552.874 254.544 ;
      RECT 0.216 255.216 552.874 255.312 ;
      RECT 0.216 255.984 552.874 256.080 ;
      RECT 0.216 256.752 552.874 256.848 ;
      RECT 0.216 257.520 552.874 257.616 ;
      RECT 0.216 258.288 552.874 258.384 ;
      RECT 0.216 259.056 552.874 259.152 ;
      RECT 0.216 259.824 552.874 259.920 ;
      RECT 0.216 260.592 552.874 260.688 ;
      RECT 0.216 261.360 552.874 261.456 ;
      RECT 0.216 262.128 552.874 262.224 ;
      RECT 0.216 262.896 552.874 262.992 ;
      RECT 0.216 263.664 552.874 263.760 ;
      RECT 0.216 264.432 552.874 264.528 ;
      RECT 0.216 265.200 552.874 265.296 ;
      RECT 0.216 265.968 552.874 266.064 ;
      RECT 0.216 266.736 552.874 266.832 ;
      RECT 0.216 267.504 552.874 267.600 ;
      RECT 0.216 268.272 552.874 268.368 ;
      RECT 0.216 269.040 552.874 269.136 ;
      RECT 0.216 269.808 552.874 269.904 ;
      RECT 0.216 270.576 552.874 270.672 ;
      RECT 0.216 271.344 552.874 271.440 ;
      RECT 0.216 272.112 552.874 272.208 ;
      RECT 0.216 272.880 552.874 272.976 ;
      RECT 0.216 273.648 552.874 273.744 ;
      RECT 0.216 274.416 552.874 274.512 ;
      RECT 0.216 275.184 552.874 275.280 ;
      RECT 0.216 275.952 552.874 276.048 ;
      RECT 0.216 276.720 552.874 276.816 ;
      RECT 0.216 277.488 552.874 277.584 ;
      RECT 0.216 278.256 552.874 278.352 ;
      RECT 0.216 279.024 552.874 279.120 ;
      RECT 0.216 279.792 552.874 279.888 ;
      RECT 0.216 280.560 552.874 280.656 ;
      RECT 0.216 281.328 552.874 281.424 ;
      RECT 0.216 282.096 552.874 282.192 ;
      RECT 0.216 282.864 552.874 282.960 ;
      RECT 0.216 283.632 552.874 283.728 ;
      RECT 0.216 284.400 552.874 284.496 ;
      RECT 0.216 285.168 552.874 285.264 ;
      RECT 0.216 285.936 552.874 286.032 ;
      RECT 0.216 286.704 552.874 286.800 ;
      RECT 0.216 287.472 552.874 287.568 ;
      RECT 0.216 288.240 552.874 288.336 ;
      RECT 0.216 289.008 552.874 289.104 ;
      RECT 0.216 289.776 552.874 289.872 ;
      RECT 0.216 290.544 552.874 290.640 ;
      RECT 0.216 291.312 552.874 291.408 ;
      RECT 0.216 292.080 552.874 292.176 ;
      RECT 0.216 292.848 552.874 292.944 ;
      RECT 0.216 293.616 552.874 293.712 ;
      RECT 0.216 294.384 552.874 294.480 ;
      RECT 0.216 295.152 552.874 295.248 ;
      RECT 0.216 295.920 552.874 296.016 ;
      RECT 0.216 296.688 552.874 296.784 ;
      RECT 0.216 297.456 552.874 297.552 ;
      RECT 0.216 298.224 552.874 298.320 ;
      RECT 0.216 298.992 552.874 299.088 ;
      RECT 0.216 299.760 552.874 299.856 ;
      RECT 0.216 300.528 552.874 300.624 ;
      RECT 0.216 301.296 552.874 301.392 ;
      RECT 0.216 302.064 552.874 302.160 ;
      RECT 0.216 302.832 552.874 302.928 ;
      RECT 0.216 303.600 552.874 303.696 ;
      RECT 0.216 304.368 552.874 304.464 ;
      RECT 0.216 305.136 552.874 305.232 ;
      RECT 0.216 305.904 552.874 306.000 ;
      RECT 0.216 306.672 552.874 306.768 ;
      RECT 0.216 307.440 552.874 307.536 ;
      RECT 0.216 308.208 552.874 308.304 ;
      RECT 0.216 308.976 552.874 309.072 ;
      RECT 0.216 309.744 552.874 309.840 ;
      RECT 0.216 310.512 552.874 310.608 ;
      RECT 0.216 311.280 552.874 311.376 ;
      RECT 0.216 312.048 552.874 312.144 ;
      RECT 0.216 312.816 552.874 312.912 ;
      RECT 0.216 313.584 552.874 313.680 ;
      RECT 0.216 314.352 552.874 314.448 ;
      RECT 0.216 315.120 552.874 315.216 ;
      RECT 0.216 315.888 552.874 315.984 ;
      RECT 0.216 316.656 552.874 316.752 ;
      RECT 0.216 317.424 552.874 317.520 ;
      RECT 0.216 318.192 552.874 318.288 ;
      RECT 0.216 318.960 552.874 319.056 ;
      RECT 0.216 319.728 552.874 319.824 ;
      RECT 0.216 320.496 552.874 320.592 ;
      RECT 0.216 321.264 552.874 321.360 ;
      RECT 0.216 322.032 552.874 322.128 ;
      RECT 0.216 322.800 552.874 322.896 ;
      RECT 0.216 323.568 552.874 323.664 ;
      RECT 0.216 324.336 552.874 324.432 ;
      RECT 0.216 325.104 552.874 325.200 ;
      RECT 0.216 325.872 552.874 325.968 ;
      RECT 0.216 326.640 552.874 326.736 ;
      RECT 0.216 327.408 552.874 327.504 ;
      RECT 0.216 328.176 552.874 328.272 ;
      RECT 0.216 328.944 552.874 329.040 ;
      RECT 0.216 329.712 552.874 329.808 ;
      RECT 0.216 330.480 552.874 330.576 ;
      RECT 0.216 331.248 552.874 331.344 ;
      RECT 0.216 332.016 552.874 332.112 ;
      RECT 0.216 332.784 552.874 332.880 ;
      RECT 0.216 333.552 552.874 333.648 ;
      RECT 0.216 334.320 552.874 334.416 ;
      RECT 0.216 335.088 552.874 335.184 ;
      RECT 0.216 335.856 552.874 335.952 ;
      RECT 0.216 336.624 552.874 336.720 ;
      RECT 0.216 337.392 552.874 337.488 ;
      RECT 0.216 338.160 552.874 338.256 ;
      RECT 0.216 338.928 552.874 339.024 ;
      RECT 0.216 339.696 552.874 339.792 ;
      RECT 0.216 340.464 552.874 340.560 ;
      RECT 0.216 341.232 552.874 341.328 ;
      RECT 0.216 342.000 552.874 342.096 ;
      RECT 0.216 342.768 552.874 342.864 ;
      RECT 0.216 343.536 552.874 343.632 ;
      RECT 0.216 344.304 552.874 344.400 ;
      RECT 0.216 345.072 552.874 345.168 ;
    END
  END VSS
  PIN VDD
    DIRECTION INOUT ;
    USE POWER ;
    PORT
      LAYER M4 ;
      RECT 0.216 0.624 552.874 0.720 ;
      RECT 0.216 1.392 552.874 1.488 ;
      RECT 0.216 2.160 552.874 2.256 ;
      RECT 0.216 2.928 552.874 3.024 ;
      RECT 0.216 3.696 552.874 3.792 ;
      RECT 0.216 4.464 552.874 4.560 ;
      RECT 0.216 5.232 552.874 5.328 ;
      RECT 0.216 6.000 552.874 6.096 ;
      RECT 0.216 6.768 552.874 6.864 ;
      RECT 0.216 7.536 552.874 7.632 ;
      RECT 0.216 8.304 552.874 8.400 ;
      RECT 0.216 9.072 552.874 9.168 ;
      RECT 0.216 9.840 552.874 9.936 ;
      RECT 0.216 10.608 552.874 10.704 ;
      RECT 0.216 11.376 552.874 11.472 ;
      RECT 0.216 12.144 552.874 12.240 ;
      RECT 0.216 12.912 552.874 13.008 ;
      RECT 0.216 13.680 552.874 13.776 ;
      RECT 0.216 14.448 552.874 14.544 ;
      RECT 0.216 15.216 552.874 15.312 ;
      RECT 0.216 15.984 552.874 16.080 ;
      RECT 0.216 16.752 552.874 16.848 ;
      RECT 0.216 17.520 552.874 17.616 ;
      RECT 0.216 18.288 552.874 18.384 ;
      RECT 0.216 19.056 552.874 19.152 ;
      RECT 0.216 19.824 552.874 19.920 ;
      RECT 0.216 20.592 552.874 20.688 ;
      RECT 0.216 21.360 552.874 21.456 ;
      RECT 0.216 22.128 552.874 22.224 ;
      RECT 0.216 22.896 552.874 22.992 ;
      RECT 0.216 23.664 552.874 23.760 ;
      RECT 0.216 24.432 552.874 24.528 ;
      RECT 0.216 25.200 552.874 25.296 ;
      RECT 0.216 25.968 552.874 26.064 ;
      RECT 0.216 26.736 552.874 26.832 ;
      RECT 0.216 27.504 552.874 27.600 ;
      RECT 0.216 28.272 552.874 28.368 ;
      RECT 0.216 29.040 552.874 29.136 ;
      RECT 0.216 29.808 552.874 29.904 ;
      RECT 0.216 30.576 552.874 30.672 ;
      RECT 0.216 31.344 552.874 31.440 ;
      RECT 0.216 32.112 552.874 32.208 ;
      RECT 0.216 32.880 552.874 32.976 ;
      RECT 0.216 33.648 552.874 33.744 ;
      RECT 0.216 34.416 552.874 34.512 ;
      RECT 0.216 35.184 552.874 35.280 ;
      RECT 0.216 35.952 552.874 36.048 ;
      RECT 0.216 36.720 552.874 36.816 ;
      RECT 0.216 37.488 552.874 37.584 ;
      RECT 0.216 38.256 552.874 38.352 ;
      RECT 0.216 39.024 552.874 39.120 ;
      RECT 0.216 39.792 552.874 39.888 ;
      RECT 0.216 40.560 552.874 40.656 ;
      RECT 0.216 41.328 552.874 41.424 ;
      RECT 0.216 42.096 552.874 42.192 ;
      RECT 0.216 42.864 552.874 42.960 ;
      RECT 0.216 43.632 552.874 43.728 ;
      RECT 0.216 44.400 552.874 44.496 ;
      RECT 0.216 45.168 552.874 45.264 ;
      RECT 0.216 45.936 552.874 46.032 ;
      RECT 0.216 46.704 552.874 46.800 ;
      RECT 0.216 47.472 552.874 47.568 ;
      RECT 0.216 48.240 552.874 48.336 ;
      RECT 0.216 49.008 552.874 49.104 ;
      RECT 0.216 49.776 552.874 49.872 ;
      RECT 0.216 50.544 552.874 50.640 ;
      RECT 0.216 51.312 552.874 51.408 ;
      RECT 0.216 52.080 552.874 52.176 ;
      RECT 0.216 52.848 552.874 52.944 ;
      RECT 0.216 53.616 552.874 53.712 ;
      RECT 0.216 54.384 552.874 54.480 ;
      RECT 0.216 55.152 552.874 55.248 ;
      RECT 0.216 55.920 552.874 56.016 ;
      RECT 0.216 56.688 552.874 56.784 ;
      RECT 0.216 57.456 552.874 57.552 ;
      RECT 0.216 58.224 552.874 58.320 ;
      RECT 0.216 58.992 552.874 59.088 ;
      RECT 0.216 59.760 552.874 59.856 ;
      RECT 0.216 60.528 552.874 60.624 ;
      RECT 0.216 61.296 552.874 61.392 ;
      RECT 0.216 62.064 552.874 62.160 ;
      RECT 0.216 62.832 552.874 62.928 ;
      RECT 0.216 63.600 552.874 63.696 ;
      RECT 0.216 64.368 552.874 64.464 ;
      RECT 0.216 65.136 552.874 65.232 ;
      RECT 0.216 65.904 552.874 66.000 ;
      RECT 0.216 66.672 552.874 66.768 ;
      RECT 0.216 67.440 552.874 67.536 ;
      RECT 0.216 68.208 552.874 68.304 ;
      RECT 0.216 68.976 552.874 69.072 ;
      RECT 0.216 69.744 552.874 69.840 ;
      RECT 0.216 70.512 552.874 70.608 ;
      RECT 0.216 71.280 552.874 71.376 ;
      RECT 0.216 72.048 552.874 72.144 ;
      RECT 0.216 72.816 552.874 72.912 ;
      RECT 0.216 73.584 552.874 73.680 ;
      RECT 0.216 74.352 552.874 74.448 ;
      RECT 0.216 75.120 552.874 75.216 ;
      RECT 0.216 75.888 552.874 75.984 ;
      RECT 0.216 76.656 552.874 76.752 ;
      RECT 0.216 77.424 552.874 77.520 ;
      RECT 0.216 78.192 552.874 78.288 ;
      RECT 0.216 78.960 552.874 79.056 ;
      RECT 0.216 79.728 552.874 79.824 ;
      RECT 0.216 80.496 552.874 80.592 ;
      RECT 0.216 81.264 552.874 81.360 ;
      RECT 0.216 82.032 552.874 82.128 ;
      RECT 0.216 82.800 552.874 82.896 ;
      RECT 0.216 83.568 552.874 83.664 ;
      RECT 0.216 84.336 552.874 84.432 ;
      RECT 0.216 85.104 552.874 85.200 ;
      RECT 0.216 85.872 552.874 85.968 ;
      RECT 0.216 86.640 552.874 86.736 ;
      RECT 0.216 87.408 552.874 87.504 ;
      RECT 0.216 88.176 552.874 88.272 ;
      RECT 0.216 88.944 552.874 89.040 ;
      RECT 0.216 89.712 552.874 89.808 ;
      RECT 0.216 90.480 552.874 90.576 ;
      RECT 0.216 91.248 552.874 91.344 ;
      RECT 0.216 92.016 552.874 92.112 ;
      RECT 0.216 92.784 552.874 92.880 ;
      RECT 0.216 93.552 552.874 93.648 ;
      RECT 0.216 94.320 552.874 94.416 ;
      RECT 0.216 95.088 552.874 95.184 ;
      RECT 0.216 95.856 552.874 95.952 ;
      RECT 0.216 96.624 552.874 96.720 ;
      RECT 0.216 97.392 552.874 97.488 ;
      RECT 0.216 98.160 552.874 98.256 ;
      RECT 0.216 98.928 552.874 99.024 ;
      RECT 0.216 99.696 552.874 99.792 ;
      RECT 0.216 100.464 552.874 100.560 ;
      RECT 0.216 101.232 552.874 101.328 ;
      RECT 0.216 102.000 552.874 102.096 ;
      RECT 0.216 102.768 552.874 102.864 ;
      RECT 0.216 103.536 552.874 103.632 ;
      RECT 0.216 104.304 552.874 104.400 ;
      RECT 0.216 105.072 552.874 105.168 ;
      RECT 0.216 105.840 552.874 105.936 ;
      RECT 0.216 106.608 552.874 106.704 ;
      RECT 0.216 107.376 552.874 107.472 ;
      RECT 0.216 108.144 552.874 108.240 ;
      RECT 0.216 108.912 552.874 109.008 ;
      RECT 0.216 109.680 552.874 109.776 ;
      RECT 0.216 110.448 552.874 110.544 ;
      RECT 0.216 111.216 552.874 111.312 ;
      RECT 0.216 111.984 552.874 112.080 ;
      RECT 0.216 112.752 552.874 112.848 ;
      RECT 0.216 113.520 552.874 113.616 ;
      RECT 0.216 114.288 552.874 114.384 ;
      RECT 0.216 115.056 552.874 115.152 ;
      RECT 0.216 115.824 552.874 115.920 ;
      RECT 0.216 116.592 552.874 116.688 ;
      RECT 0.216 117.360 552.874 117.456 ;
      RECT 0.216 118.128 552.874 118.224 ;
      RECT 0.216 118.896 552.874 118.992 ;
      RECT 0.216 119.664 552.874 119.760 ;
      RECT 0.216 120.432 552.874 120.528 ;
      RECT 0.216 121.200 552.874 121.296 ;
      RECT 0.216 121.968 552.874 122.064 ;
      RECT 0.216 122.736 552.874 122.832 ;
      RECT 0.216 123.504 552.874 123.600 ;
      RECT 0.216 124.272 552.874 124.368 ;
      RECT 0.216 125.040 552.874 125.136 ;
      RECT 0.216 125.808 552.874 125.904 ;
      RECT 0.216 126.576 552.874 126.672 ;
      RECT 0.216 127.344 552.874 127.440 ;
      RECT 0.216 128.112 552.874 128.208 ;
      RECT 0.216 128.880 552.874 128.976 ;
      RECT 0.216 129.648 552.874 129.744 ;
      RECT 0.216 130.416 552.874 130.512 ;
      RECT 0.216 131.184 552.874 131.280 ;
      RECT 0.216 131.952 552.874 132.048 ;
      RECT 0.216 132.720 552.874 132.816 ;
      RECT 0.216 133.488 552.874 133.584 ;
      RECT 0.216 134.256 552.874 134.352 ;
      RECT 0.216 135.024 552.874 135.120 ;
      RECT 0.216 135.792 552.874 135.888 ;
      RECT 0.216 136.560 552.874 136.656 ;
      RECT 0.216 137.328 552.874 137.424 ;
      RECT 0.216 138.096 552.874 138.192 ;
      RECT 0.216 138.864 552.874 138.960 ;
      RECT 0.216 139.632 552.874 139.728 ;
      RECT 0.216 140.400 552.874 140.496 ;
      RECT 0.216 141.168 552.874 141.264 ;
      RECT 0.216 141.936 552.874 142.032 ;
      RECT 0.216 142.704 552.874 142.800 ;
      RECT 0.216 143.472 552.874 143.568 ;
      RECT 0.216 144.240 552.874 144.336 ;
      RECT 0.216 145.008 552.874 145.104 ;
      RECT 0.216 145.776 552.874 145.872 ;
      RECT 0.216 146.544 552.874 146.640 ;
      RECT 0.216 147.312 552.874 147.408 ;
      RECT 0.216 148.080 552.874 148.176 ;
      RECT 0.216 148.848 552.874 148.944 ;
      RECT 0.216 149.616 552.874 149.712 ;
      RECT 0.216 150.384 552.874 150.480 ;
      RECT 0.216 151.152 552.874 151.248 ;
      RECT 0.216 151.920 552.874 152.016 ;
      RECT 0.216 152.688 552.874 152.784 ;
      RECT 0.216 153.456 552.874 153.552 ;
      RECT 0.216 154.224 552.874 154.320 ;
      RECT 0.216 154.992 552.874 155.088 ;
      RECT 0.216 155.760 552.874 155.856 ;
      RECT 0.216 156.528 552.874 156.624 ;
      RECT 0.216 157.296 552.874 157.392 ;
      RECT 0.216 158.064 552.874 158.160 ;
      RECT 0.216 158.832 552.874 158.928 ;
      RECT 0.216 159.600 552.874 159.696 ;
      RECT 0.216 160.368 552.874 160.464 ;
      RECT 0.216 161.136 552.874 161.232 ;
      RECT 0.216 161.904 552.874 162.000 ;
      RECT 0.216 162.672 552.874 162.768 ;
      RECT 0.216 163.440 552.874 163.536 ;
      RECT 0.216 164.208 552.874 164.304 ;
      RECT 0.216 164.976 552.874 165.072 ;
      RECT 0.216 165.744 552.874 165.840 ;
      RECT 0.216 166.512 552.874 166.608 ;
      RECT 0.216 167.280 552.874 167.376 ;
      RECT 0.216 168.048 552.874 168.144 ;
      RECT 0.216 168.816 552.874 168.912 ;
      RECT 0.216 169.584 552.874 169.680 ;
      RECT 0.216 170.352 552.874 170.448 ;
      RECT 0.216 171.120 552.874 171.216 ;
      RECT 0.216 171.888 552.874 171.984 ;
      RECT 0.216 172.656 552.874 172.752 ;
      RECT 0.216 173.424 552.874 173.520 ;
      RECT 0.216 174.192 552.874 174.288 ;
      RECT 0.216 174.960 552.874 175.056 ;
      RECT 0.216 175.728 552.874 175.824 ;
      RECT 0.216 176.496 552.874 176.592 ;
      RECT 0.216 177.264 552.874 177.360 ;
      RECT 0.216 178.032 552.874 178.128 ;
      RECT 0.216 178.800 552.874 178.896 ;
      RECT 0.216 179.568 552.874 179.664 ;
      RECT 0.216 180.336 552.874 180.432 ;
      RECT 0.216 181.104 552.874 181.200 ;
      RECT 0.216 181.872 552.874 181.968 ;
      RECT 0.216 182.640 552.874 182.736 ;
      RECT 0.216 183.408 552.874 183.504 ;
      RECT 0.216 184.176 552.874 184.272 ;
      RECT 0.216 184.944 552.874 185.040 ;
      RECT 0.216 185.712 552.874 185.808 ;
      RECT 0.216 186.480 552.874 186.576 ;
      RECT 0.216 187.248 552.874 187.344 ;
      RECT 0.216 188.016 552.874 188.112 ;
      RECT 0.216 188.784 552.874 188.880 ;
      RECT 0.216 189.552 552.874 189.648 ;
      RECT 0.216 190.320 552.874 190.416 ;
      RECT 0.216 191.088 552.874 191.184 ;
      RECT 0.216 191.856 552.874 191.952 ;
      RECT 0.216 192.624 552.874 192.720 ;
      RECT 0.216 193.392 552.874 193.488 ;
      RECT 0.216 194.160 552.874 194.256 ;
      RECT 0.216 194.928 552.874 195.024 ;
      RECT 0.216 195.696 552.874 195.792 ;
      RECT 0.216 196.464 552.874 196.560 ;
      RECT 0.216 197.232 552.874 197.328 ;
      RECT 0.216 198.000 552.874 198.096 ;
      RECT 0.216 198.768 552.874 198.864 ;
      RECT 0.216 199.536 552.874 199.632 ;
      RECT 0.216 200.304 552.874 200.400 ;
      RECT 0.216 201.072 552.874 201.168 ;
      RECT 0.216 201.840 552.874 201.936 ;
      RECT 0.216 202.608 552.874 202.704 ;
      RECT 0.216 203.376 552.874 203.472 ;
      RECT 0.216 204.144 552.874 204.240 ;
      RECT 0.216 204.912 552.874 205.008 ;
      RECT 0.216 205.680 552.874 205.776 ;
      RECT 0.216 206.448 552.874 206.544 ;
      RECT 0.216 207.216 552.874 207.312 ;
      RECT 0.216 207.984 552.874 208.080 ;
      RECT 0.216 208.752 552.874 208.848 ;
      RECT 0.216 209.520 552.874 209.616 ;
      RECT 0.216 210.288 552.874 210.384 ;
      RECT 0.216 211.056 552.874 211.152 ;
      RECT 0.216 211.824 552.874 211.920 ;
      RECT 0.216 212.592 552.874 212.688 ;
      RECT 0.216 213.360 552.874 213.456 ;
      RECT 0.216 214.128 552.874 214.224 ;
      RECT 0.216 214.896 552.874 214.992 ;
      RECT 0.216 215.664 552.874 215.760 ;
      RECT 0.216 216.432 552.874 216.528 ;
      RECT 0.216 217.200 552.874 217.296 ;
      RECT 0.216 217.968 552.874 218.064 ;
      RECT 0.216 218.736 552.874 218.832 ;
      RECT 0.216 219.504 552.874 219.600 ;
      RECT 0.216 220.272 552.874 220.368 ;
      RECT 0.216 221.040 552.874 221.136 ;
      RECT 0.216 221.808 552.874 221.904 ;
      RECT 0.216 222.576 552.874 222.672 ;
      RECT 0.216 223.344 552.874 223.440 ;
      RECT 0.216 224.112 552.874 224.208 ;
      RECT 0.216 224.880 552.874 224.976 ;
      RECT 0.216 225.648 552.874 225.744 ;
      RECT 0.216 226.416 552.874 226.512 ;
      RECT 0.216 227.184 552.874 227.280 ;
      RECT 0.216 227.952 552.874 228.048 ;
      RECT 0.216 228.720 552.874 228.816 ;
      RECT 0.216 229.488 552.874 229.584 ;
      RECT 0.216 230.256 552.874 230.352 ;
      RECT 0.216 231.024 552.874 231.120 ;
      RECT 0.216 231.792 552.874 231.888 ;
      RECT 0.216 232.560 552.874 232.656 ;
      RECT 0.216 233.328 552.874 233.424 ;
      RECT 0.216 234.096 552.874 234.192 ;
      RECT 0.216 234.864 552.874 234.960 ;
      RECT 0.216 235.632 552.874 235.728 ;
      RECT 0.216 236.400 552.874 236.496 ;
      RECT 0.216 237.168 552.874 237.264 ;
      RECT 0.216 237.936 552.874 238.032 ;
      RECT 0.216 238.704 552.874 238.800 ;
      RECT 0.216 239.472 552.874 239.568 ;
      RECT 0.216 240.240 552.874 240.336 ;
      RECT 0.216 241.008 552.874 241.104 ;
      RECT 0.216 241.776 552.874 241.872 ;
      RECT 0.216 242.544 552.874 242.640 ;
      RECT 0.216 243.312 552.874 243.408 ;
      RECT 0.216 244.080 552.874 244.176 ;
      RECT 0.216 244.848 552.874 244.944 ;
      RECT 0.216 245.616 552.874 245.712 ;
      RECT 0.216 246.384 552.874 246.480 ;
      RECT 0.216 247.152 552.874 247.248 ;
      RECT 0.216 247.920 552.874 248.016 ;
      RECT 0.216 248.688 552.874 248.784 ;
      RECT 0.216 249.456 552.874 249.552 ;
      RECT 0.216 250.224 552.874 250.320 ;
      RECT 0.216 250.992 552.874 251.088 ;
      RECT 0.216 251.760 552.874 251.856 ;
      RECT 0.216 252.528 552.874 252.624 ;
      RECT 0.216 253.296 552.874 253.392 ;
      RECT 0.216 254.064 552.874 254.160 ;
      RECT 0.216 254.832 552.874 254.928 ;
      RECT 0.216 255.600 552.874 255.696 ;
      RECT 0.216 256.368 552.874 256.464 ;
      RECT 0.216 257.136 552.874 257.232 ;
      RECT 0.216 257.904 552.874 258.000 ;
      RECT 0.216 258.672 552.874 258.768 ;
      RECT 0.216 259.440 552.874 259.536 ;
      RECT 0.216 260.208 552.874 260.304 ;
      RECT 0.216 260.976 552.874 261.072 ;
      RECT 0.216 261.744 552.874 261.840 ;
      RECT 0.216 262.512 552.874 262.608 ;
      RECT 0.216 263.280 552.874 263.376 ;
      RECT 0.216 264.048 552.874 264.144 ;
      RECT 0.216 264.816 552.874 264.912 ;
      RECT 0.216 265.584 552.874 265.680 ;
      RECT 0.216 266.352 552.874 266.448 ;
      RECT 0.216 267.120 552.874 267.216 ;
      RECT 0.216 267.888 552.874 267.984 ;
      RECT 0.216 268.656 552.874 268.752 ;
      RECT 0.216 269.424 552.874 269.520 ;
      RECT 0.216 270.192 552.874 270.288 ;
      RECT 0.216 270.960 552.874 271.056 ;
      RECT 0.216 271.728 552.874 271.824 ;
      RECT 0.216 272.496 552.874 272.592 ;
      RECT 0.216 273.264 552.874 273.360 ;
      RECT 0.216 274.032 552.874 274.128 ;
      RECT 0.216 274.800 552.874 274.896 ;
      RECT 0.216 275.568 552.874 275.664 ;
      RECT 0.216 276.336 552.874 276.432 ;
      RECT 0.216 277.104 552.874 277.200 ;
      RECT 0.216 277.872 552.874 277.968 ;
      RECT 0.216 278.640 552.874 278.736 ;
      RECT 0.216 279.408 552.874 279.504 ;
      RECT 0.216 280.176 552.874 280.272 ;
      RECT 0.216 280.944 552.874 281.040 ;
      RECT 0.216 281.712 552.874 281.808 ;
      RECT 0.216 282.480 552.874 282.576 ;
      RECT 0.216 283.248 552.874 283.344 ;
      RECT 0.216 284.016 552.874 284.112 ;
      RECT 0.216 284.784 552.874 284.880 ;
      RECT 0.216 285.552 552.874 285.648 ;
      RECT 0.216 286.320 552.874 286.416 ;
      RECT 0.216 287.088 552.874 287.184 ;
      RECT 0.216 287.856 552.874 287.952 ;
      RECT 0.216 288.624 552.874 288.720 ;
      RECT 0.216 289.392 552.874 289.488 ;
      RECT 0.216 290.160 552.874 290.256 ;
      RECT 0.216 290.928 552.874 291.024 ;
      RECT 0.216 291.696 552.874 291.792 ;
      RECT 0.216 292.464 552.874 292.560 ;
      RECT 0.216 293.232 552.874 293.328 ;
      RECT 0.216 294.000 552.874 294.096 ;
      RECT 0.216 294.768 552.874 294.864 ;
      RECT 0.216 295.536 552.874 295.632 ;
      RECT 0.216 296.304 552.874 296.400 ;
      RECT 0.216 297.072 552.874 297.168 ;
      RECT 0.216 297.840 552.874 297.936 ;
      RECT 0.216 298.608 552.874 298.704 ;
      RECT 0.216 299.376 552.874 299.472 ;
      RECT 0.216 300.144 552.874 300.240 ;
      RECT 0.216 300.912 552.874 301.008 ;
      RECT 0.216 301.680 552.874 301.776 ;
      RECT 0.216 302.448 552.874 302.544 ;
      RECT 0.216 303.216 552.874 303.312 ;
      RECT 0.216 303.984 552.874 304.080 ;
      RECT 0.216 304.752 552.874 304.848 ;
      RECT 0.216 305.520 552.874 305.616 ;
      RECT 0.216 306.288 552.874 306.384 ;
      RECT 0.216 307.056 552.874 307.152 ;
      RECT 0.216 307.824 552.874 307.920 ;
      RECT 0.216 308.592 552.874 308.688 ;
      RECT 0.216 309.360 552.874 309.456 ;
      RECT 0.216 310.128 552.874 310.224 ;
      RECT 0.216 310.896 552.874 310.992 ;
      RECT 0.216 311.664 552.874 311.760 ;
      RECT 0.216 312.432 552.874 312.528 ;
      RECT 0.216 313.200 552.874 313.296 ;
      RECT 0.216 313.968 552.874 314.064 ;
      RECT 0.216 314.736 552.874 314.832 ;
      RECT 0.216 315.504 552.874 315.600 ;
      RECT 0.216 316.272 552.874 316.368 ;
      RECT 0.216 317.040 552.874 317.136 ;
      RECT 0.216 317.808 552.874 317.904 ;
      RECT 0.216 318.576 552.874 318.672 ;
      RECT 0.216 319.344 552.874 319.440 ;
      RECT 0.216 320.112 552.874 320.208 ;
      RECT 0.216 320.880 552.874 320.976 ;
      RECT 0.216 321.648 552.874 321.744 ;
      RECT 0.216 322.416 552.874 322.512 ;
      RECT 0.216 323.184 552.874 323.280 ;
      RECT 0.216 323.952 552.874 324.048 ;
      RECT 0.216 324.720 552.874 324.816 ;
      RECT 0.216 325.488 552.874 325.584 ;
      RECT 0.216 326.256 552.874 326.352 ;
      RECT 0.216 327.024 552.874 327.120 ;
      RECT 0.216 327.792 552.874 327.888 ;
      RECT 0.216 328.560 552.874 328.656 ;
      RECT 0.216 329.328 552.874 329.424 ;
      RECT 0.216 330.096 552.874 330.192 ;
      RECT 0.216 330.864 552.874 330.960 ;
      RECT 0.216 331.632 552.874 331.728 ;
      RECT 0.216 332.400 552.874 332.496 ;
      RECT 0.216 333.168 552.874 333.264 ;
      RECT 0.216 333.936 552.874 334.032 ;
      RECT 0.216 334.704 552.874 334.800 ;
      RECT 0.216 335.472 552.874 335.568 ;
      RECT 0.216 336.240 552.874 336.336 ;
      RECT 0.216 337.008 552.874 337.104 ;
      RECT 0.216 337.776 552.874 337.872 ;
      RECT 0.216 338.544 552.874 338.640 ;
      RECT 0.216 339.312 552.874 339.408 ;
      RECT 0.216 340.080 552.874 340.176 ;
      RECT 0.216 340.848 552.874 340.944 ;
      RECT 0.216 341.616 552.874 341.712 ;
      RECT 0.216 342.384 552.874 342.480 ;
      RECT 0.216 343.152 552.874 343.248 ;
      RECT 0.216 343.920 552.874 344.016 ;
      RECT 0.216 344.688 552.874 344.784 ;
      RECT 0.216 345.456 552.874 345.552 ;
    END
  END VDD
  OBS
    LAYER M1 ;
    RECT 0 0 553.090 345.800 ;
    LAYER M2 ;
    RECT 0 0 553.090 345.800 ;
    LAYER M3 ;
    RECT 0 0 553.090 345.800 ;
    LAYER M4 ;
    RECT 0 0 553.090 345.800 ;
  END
END fakeram_w64_l16384

END LIBRARY
